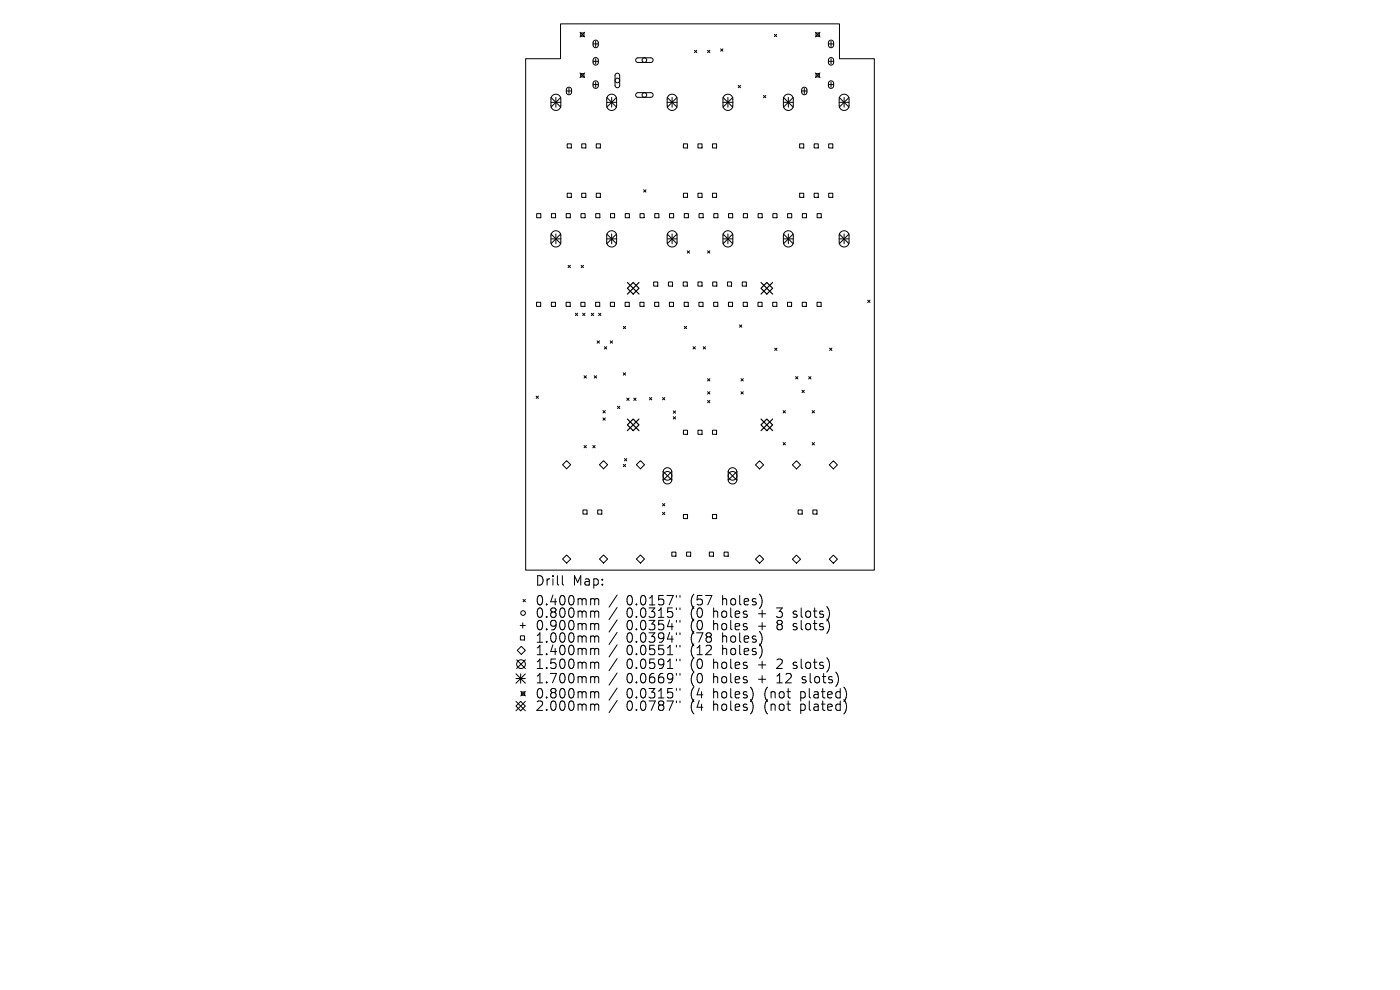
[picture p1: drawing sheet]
<svg xmlns="http://www.w3.org/2000/svg" width="297mm" height="210mm" viewBox="0 0 297 210" stroke-linecap="round" stroke-linejoin="round" font-family="sans-serif">
<defs><g id="words">
<g font-size="2.8">
<text x="113.5" y="124.5">Drill</text>
<text x="121.5" y="124.5">Map:</text>
<text x="113.5" y="128.7">0.400mm</text>
<text x="113.5" y="131.3">0.800mm</text>
<text x="132.9" y="128.7">0.0157&quot;</text>
<text x="132.9" y="131.3">0.0315&quot;</text>
<text x="146.6" y="128.7">(57</text>
<text x="146.6" y="131.3">(0</text>
<text x="151.6" y="131.3">holes</text>
<text x="153.5" y="128.7">holes)</text>
<text x="161.3" y="131.3">+</text>
<text x="165.5" y="131.3">3</text>
<text x="169.1" y="131.3">slots)</text>
<text x="113.5" y="134">0.900mm</text>
<text x="113.5" y="136.6">1.000mm</text>
<text x="132.9" y="134">0.0354&quot;</text>
<text x="132.9" y="136.6">0.0394&quot;</text>
<text x="146.6" y="134">(0</text>
<text x="146.6" y="136.6">(78</text>
<text x="151.6" y="134">holes</text>
<text x="153.5" y="136.6">holes)</text>
<text x="161.3" y="134">+</text>
<text x="165.5" y="134">8</text>
<text x="169.1" y="134">slots)</text>
<text x="113.5" y="139.3">1.400mm</text>
<text x="113.5" y="142.2">1.500mm</text>
<text x="132.9" y="139.3">0.0551&quot;</text>
<text x="132.9" y="142.2">0.0591&quot;</text>
<text x="146.6" y="139.3">(12</text>
<text x="146.6" y="142.2">(0</text>
<text x="151.6" y="142.2">holes</text>
<text x="153.5" y="139.3">holes)</text>
<text x="161.3" y="142.2">+</text>
<text x="165.5" y="142.2">2</text>
<text x="169.1" y="142.2">slots)</text>
<text x="113.5" y="145.2">1.700mm</text>
<text x="113.5" y="148.4">0.800mm</text>
<text x="132.9" y="145.2">0.0669&quot;</text>
<text x="132.9" y="148.4">0.0315&quot;</text>
<text x="146.6" y="145.2">(0</text>
<text x="146.6" y="148.4">(4</text>
<text x="151.6" y="145.2">holes</text>
<text x="151.6" y="148.4">holes)</text>
<text x="161.3" y="145.2">+</text>
<text x="162.6" y="148.4">(not</text>
<text x="165.5" y="145.2">12</text>
<text x="170.5" y="148.4">plated)</text>
<text x="171" y="145.2">slots)</text>
<text x="113.5" y="151.1">2.000mm</text>
<text x="132.9" y="151.1">0.0787&quot;</text>
<text x="146.6" y="151.1">(4</text>
<text x="151.6" y="151.1">holes)</text>
<text x="162.6" y="151.1">(not</text>
<text x="170.5" y="151.1">plated)</text>
</g>
</g></defs>
<g fill="none" stroke="#000" stroke-width=".21">
<path d="M118.9 5.1h59.2v7.4h7.4v108.4h-74v-108.4h7.4zM120.1 19.3h1.2M120.3 18.7l.5-.2 .4 .3v.8l-.3 .4-.4 .1-.3-.3-.1-.8zM120.7 18.7v1.2M123 6.8l1 1M123 15.5l1 1M123.2 7h.7v.7h-.7zM123.2 15.6h.7v.7h-.7zM124 6.8l-1 1M124 15.5l-1 1M125.8 9.3h1.1M125.8 13h1.1"/>
<path d="M125.8 17.9h1.1M126 8.7l.5-.2 .4 .3v.9l-.3 .4h-.4l-.3-.3-.1-.8zM126 12.4l.5-.2 .4 .3v.9l-.3 .4h-.4l-.3-.3-.1-.8zM126 17.3l.5-.1 .4 .3v.8l-.3 .4h-.4l-.3-.3-.1-.8zM126.4 8.8v1.1M126.4 12.5v1.1M126.4 17.4v1.1M130.6 15.7l.5-.1 .4 .3v2.3l-.4 .4-.4-.1-.2-.3v-2.2zM135 12.4l.3-.1h2.8l.3 .1 .2 .4-.5 .4h-2.8l-.4-.3zM135 19.8l.3-.1h2.8l.3 .1 .2 .4-.5 .4h-2.8l-.4-.3zM147.3 10.7l.5 .5M147.8 10.7l-.5 .5"/>
<path d="M150.1 10.7l.5 .5M150.6 10.7l-.5 .5M152.9 10.4l.5 .5M153.4 10.4l-.5 .5M156.6 18.1l.5 .5M157.1 18.1l-.5 .5M164.3 7.3l.5 .5M164.8 7.3l-.5 .5M170.1 19.3h1.1M170.2 18.7l.5-.2 .4 .3 .1 .8-.3 .4-.5 .1-.3-.3v-.8zM170.6 18.7v1.2M173 6.8l1 1"/>
<path d="M173 15.5l1 1M173.1 7h.7v.7h-.7zM173.1 15.6h.7v.7h-.7zM174 6.8l-1 1M174 15.5l-1 1M175.7 9.3h1.2M175.7 13h1.2M175.7 17.9h1.2M175.9 8.7l.5-.2 .4 .3v.9l-.3 .4h-.4l-.3-.3-.1-.8zM175.9 12.4l.5-.2 .4 .3v.9l-.3 .4h-.4l-.3-.3-.1-.8zM175.9 17.3l.5-.1 .4 .3v.8l-.3 .4h-.4l-.3-.3-.1-.8zM176.3 8.8v1.1"/>
<path d="M176.3 12.5v1.1M176.3 17.4v1.1M116.9 20.7l2.1 2.1M116.9 21.7h2.1M117.2 20.3a1.05 1.05 0 0 1 1.1-.2 1.05 1.05 0 0 1 .7 .9v1.4a1.05 1.05 0 0 1-1.1 1 1.05 1.05 0 0 1-1-1v-1.6zM117.9 20.7v2.1M119 20.7l-2.1 2.1M120.3 30.5h.9v.9h-.9zM123.4 30.5h.9v.9h-.9zM126.5 30.5h.9v.9h-.9zM128.7 21.7h2.1M128.7 20.7l2.1 2.1"/>
<path d="M129 20.3a1.05 1.05 0 0 1 1.2-.2 1.05 1.05 0 0 1 .6 .9v1.4a1.05 1.05 0 0 1-1 1 1.05 1.05 0 0 1-1.1-1v-1.6zM129.8 20.7v2.1M130.8 20.7l-2.1 2.1M141.5 21.7h2.1M141.5 20.7l2.1 2.1M141.8 20.3a1.05 1.05 0 0 1 1.2-.2 1.05 1.05 0 0 1 .6 .9v1.4a1.05 1.05 0 0 1-1 1 1.05 1.05 0 0 1-1.1-1l.1-1.6zM142.6 20.7v2.1M143.6 20.7l-2.1 2.1M145 30.5h.9v.9h-.9zM148.1 30.5h.8v.9h-.8zM151.1 30.5h.9v.9h-.9zM153.4 21.7h2.1"/>
<path d="M153.4 20.7l2.1 2.1M153.7 20.3a1.05 1.05 0 0 1 1.1-.2 1.05 1.05 0 0 1 .7 .9v1.4a1.05 1.05 0 0 1-1.1 1 1.05 1.05 0 0 1-1-1v-1.6zM154.4 20.7v2.1M155.5 20.7l-2.1 2.1M162 20.2l.5 .5M162.5 20.2l-.5 .5M166.2 21.7h2.1M166.2 20.7l2.1 2.1M166.5 20.3a1.05 1.05 0 0 1 1.1-.2 1.05 1.05 0 0 1 .7 .9v1.4a1.05 1.05 0 0 1-1.1 1 1.05 1.05 0 0 1-1-1v-1.6zM167.2 20.7v2.1M168.3 20.7l-2.1 2.1M169.6 30.5h.9v.9h-.9z"/>
<path d="M172.7 30.5h.9v.9h-.9zM175.8 30.5h.9v.9h-.9zM178 21.7h2.1M178 20.7l2.1 2.1M178.3 20.3a1.05 1.05 0 0 1 1.2-.2 1.05 1.05 0 0 1 .6 .9v1.4a1.05 1.05 0 0 1-1 1 1.05 1.05 0 0 1-1.1-1v-1.6zM179.1 20.7v2.1M180.1 20.7l-2.1 2.1M113.9 45.3h.8v.9h-.8zM116.9 49.6l2.1 2.1M116.9 50.7h2.1M117 45.3h.9v.9h-.9zM117.2 49.3a1.05 1.05 0 0 1 1.1-.3 1.05 1.05 0 0 1 .7 1v1.4a1.05 1.05 0 0 1-1.1 1 1.05 1.05 0 0 1-1-1v-1.6z"/>
<path d="M117.9 49.6v2.1M119 49.6l-2.1 2.1M120.1 45.3h.9v.9h-.9zM120.3 41h.9v.9h-.9zM120.5 56.3l.5 .5M121 56.3l-.5 .5M123.2 45.3h.9v.9h-.9zM123.3 56.3l.5 .5M123.4 41h.9v.9h-.9zM123.8 56.3l-.5 .5M126.4 45.3h.9v.9h-.9zM126.5 41h.9v.9h-.9z"/>
<path d="M128.7 50.7h2.1M128.7 49.6l2.1 2.1M129 49.3a1.05 1.05 0 0 1 1.2-.3 1.05 1.05 0 0 1 .6 1v1.4a1.05 1.05 0 0 1-1 1 1.05 1.05 0 0 1-1.1-1v-1.6zM129.5 45.3h.9v.9h-.9zM129.8 49.6v2.1M130.8 49.6l-2.1 2.1M132.6 45.3h.9v.9h-.9zM135.8 45.3h.8v.9h-.8zM136.5 40.3l.5 .5M137 40.3l-.5 .5M138.7 59.8h.8v.9h-.8zM138.9 45.3h.9v.9h-.9z"/>
<path d="M141.5 50.7h2.1M141.5 49.6l2.1 2.1M141.8 59.8h.9v.9h-.9zM141.8 49.3a1.05 1.05 0 0 1 1.2-.3 1.05 1.05 0 0 1 .6 1v1.4a1.05 1.05 0 0 1-1 1 1.05 1.05 0 0 1-1.1-1l.1-1.6zM142 45.3h.9v.9h-.9zM142.6 49.6v2.1M143.6 49.6l-2.1 2.1M144.9 59.8h.9v.9h-.9zM145 41h.9v.9h-.9zM145.2 45.3h.8v.9h-.8zM145.8 53.2l.5 .5M146.3 53.2l-.5 .5"/>
<path d="M148.1 41h.8v.9h-.8zM148.1 59.8h.8v.9h-.8zM148.3 45.3h.9v.9h-.9zM150.1 53.2l.5 .5M150.6 53.2l-.5 .5M151.1 41h.9v.9h-.9zM151.2 59.8h.9v.9h-.9zM151.4 45.3h.9v.9h-.9zM153.4 50.7h2.1M153.4 49.6l2.1 2.1M153.7 49.3a1.05 1.05 0 0 1 1.1-.3 1.05 1.05 0 0 1 .7 1v1.4a1.05 1.05 0 0 1-1.1 1 1.05 1.05 0 0 1-1-1v-1.6zM154.3 59.8h.9v.9h-.9z"/>
<path d="M154.4 49.6v2.1M154.6 45.3h.8v.9h-.8zM155.5 49.6l-2.1 2.1M157.5 59.8h.8v.9h-.8zM157.7 45.3h.9v.9h-.9zM160.8 45.3h.9v.9h-.9zM164 45.3h.8v.9h-.8zM166.2 50.7h2.1M166.2 49.6l2.1 2.1M166.5 49.3a1.05 1.05 0 0 1 1.1-.3 1.05 1.05 0 0 1 .7 1v1.4a1.05 1.05 0 0 1-1.1 1 1.05 1.05 0 0 1-1-1v-1.6zM167.1 45.3h.9v.9h-.9zM167.2 49.6v2.1"/>
<path d="M168.3 49.6l-2.1 2.1M169.6 41h.9v.9h-.9zM170.2 45.3h.9v.9h-.9zM172.7 41h.9v.9h-.9zM173.3 45.3h.9v.9h-.9zM175.8 41h.9v.9h-.9zM178 50.7h2.1M178 49.6l2.1 2.1M178.3 49.3a1.05 1.05 0 0 1 1.2-.3 1.05 1.05 0 0 1 .6 1v1.4a1.05 1.05 0 0 1-1 1 1.05 1.05 0 0 1-1.1-1v-1.6zM179.1 49.6v2.1M180.1 49.6l-2.1 2.1M113.8 64.1h.9v.9h-.9z"/>
<path d="M117 64.1h.8v.9h-.8zM120.1 64.1h.9v.9h-.9zM122.1 66.5l.5 .4M122.6 66.5l-.5 .4M123.2 64.1h.9v.9h-.9zM123.6 66.5l.5 .4M123.9 79.7l.5 .5M124.1 66.5l-.5 .4M124.4 79.7l-.5 .5M125.4 66.5l.5 .4M125.9 66.5l-.5 .4M126.1 79.7l.5 .5"/>
<path d="M126.4 64.1h.8v.9h-.8zM126.6 79.7l-.5 .5M126.7 72.3l.5 .5M127 66.5l.5 .4M127.2 72.3l-.5 .5M127.5 66.5l-.5 .4M128.2 73.5l.5 .5M128.7 73.5l-.5 .5M129.5 72.3l.4 .5M129.5 64.1h.9v.9h-.9zM129.9 72.3l-.4 .5M132.2 69.2l.5 .5"/>
<path d="M132.2 79.1l.5 .5M132.6 64.1h.9v.9h-.9zM132.7 69.2l-.5 .5M132.7 79.1l-.5 .5M135.7 64.1h.9v.9h-.9zM138.9 64.1h.9v.9h-.9zM142 64.1h.9v.9h-.9zM145.1 64.1h.9v.9h-.9zM145.2 69.2l.5 .5M145.7 69.2l-.5 .5M147 73.5l.5 .5M147.5 73.5l-.5 .5"/>
<path d="M148.3 64.1h.8v.9h-.8zM149.2 73.5l.5 .5M149.7 73.5l-.5 .5M151.4 64.1h.9v.9h-.9zM154.5 64.1h.9v.9h-.9zM156.9 68.9l.5 .5M157.4 68.9l-.5 .5M157.7 64.1h.8v.9h-.8zM160.8 64.1h.9v.9h-.9zM163.9 64.1h.9v.9h-.9zM164.3 73.9l.5 .4M164.8 73.9l-.5 .4"/>
<path d="M167.1 64.1h.8v.9h-.8zM168.8 79.9l.5 .5M169.3 79.9l-.5 .5M170.2 64.1h.9v.9h-.9zM171.6 79.9l.4 .5M172 79.9l-.4 .5M173.3 64.1h.9v.9h-.9zM176 73.9l.5 .4M176.5 73.9l-.5 .4M184.1 63.7l.5 .5M184.6 63.7l-.5 .5M113.7 84l.5 .5"/>
<path d="M114.2 84l-.5 .5M119.3 98.6l.9-.9 .9 .9-.9 .8zM123.9 94.5l.5 .5M124.4 94.5l-.5 .5M125.8 94.5l.4 .5M126.2 94.5l-.4 .5M127.2 98.6l.8-.9 .9 .9-.9 .8zM127.9 87.1l.5 .5M127.9 88.6l.5 .5M128.4 87.1l-.5 .5M128.4 88.6l-.5 .5M131 86.2l.5 .5"/>
<path d="M131.5 86.2l-.5 .5M132.2 98.5l.5 .5M132.5 97.3l.5 .5M132.7 98.5l-.5 .5M133 97.3l-.5 .5M133 84.5l.5 .4M133.5 84.5l-.5 .4M134.4 84.5l.5 .4M134.9 84.5l-.5 .4M135 98.6l.9-.9 .8 .9-.8 .8zM137.8 84.3l.5 .5M138.3 84.3l-.5 .5"/>
<path d="M140.5 84.3l.5 .5M140.9 99.5a.92 .92 0 0 1 1.1-.2 .92 .92 0 0 1 .5 .8v1.6a.92 .92 0 0 1-.9 1 .92 .92 0 0 1-.9-1v-1.6zM141 84.3l-.5 .5M142.8 87.2l.5 .5M142.8 88.4l.5 .5M143.3 87.2l-.5 .5M143.3 88.4l-.5 .5M145 91.3h.9v.8h-.9zM148.1 91.3h.8v.8h-.8zM150.1 80.3l.5 .5M150.1 83.1l.5 .5M150.1 84.9l.5 .5"/>
<path d="M150.6 80.3l-.5 .5M150.6 83.1l-.5 .5M150.6 84.9l-.5 .5M151.1 91.3h.9v.8h-.9zM154.8 99.5a.92 .92 0 0 1 1-.2 .92 .92 0 0 1 .5 .8v1.6a.92 .92 0 0 1-.9 1 .92 .92 0 0 1-.9-1v-1.6zM157.2 80.3l.5 .5M157.2 83.1l.5 .5M157.7 80.3l-.5 .5M157.7 83.1l-.5 .5M160.3 98.6l.8-.9 .9 .9-.9 .9zM166.1 87.1l.5 .5M166.1 93.9l.5 .5"/>
<path d="M166.6 87.1l-.5 .5M166.6 93.9l-.5 .5M168.1 98.6l.9-.9 .8 .9-.8 .9zM170.1 82.8l.5 .5M170.6 82.8l-.5 .5M172.3 87.1l.5 .5M172.3 93.9l.5 .5M172.8 87.1l-.5 .5M172.8 93.9l-.5 .5M175.9 98.6l.9-.9 .9 .9-.9 .9zM119.3 118.6l.9-.9 .9 .9-.9 .9zM123.7 108.2h.8v.9h-.8z"/>
<path d="M126.8 108.2h.9v.9h-.9zM127.2 118.6l.8-.9 .9 .9-.9 .9zM135 118.6l.9-.9 .8 .9-.8 .9zM140.5 106.8l.5 .5M140.5 108.7l.5 .5M140.7 100l1.8 1.9M141 106.8l-.5 .5M141 108.7l-.5 .5M142.5 117.1h.9v.9h-.9zM142.5 100l-1.8 1.9M145 109.1h.9v.9h-.9zM145.6 117.1h.9v.9h-.9z"/>
<path d="M150.5 117.1h.9v.9h-.9zM151.1 109.1h.9v.9h-.9zM153.6 117.1h.9v.9h-.9zM154.5 100l1.8 1.9M156.3 100l-1.8 1.9M160.3 118.6l.8-.8 .9 .8-.9 .9zM168.1 118.6l.9-.8 .8 .8-.8 .9zM169.3 108.2h.9v.9h-.9zM172.4 108.2h.9v.9h-.9zM175.9 118.6l.9-.8 .9 .8-.9 .9zM109.6 140l1.9 1.8M109.7 138l.9-.9 .9 .9-.9 .8z"/>
<path d="M110.3 132.7h1.2M110.4 134.9h.9v.9h-.9zM110.9 132.1v1.1M111 127.2l.5 .5M111.5 127.2l-.5 .5M111.5 140l-1.9 1.8M119.3 122.1v1.7l.3 .3M125.6 127h.3l.3 .3M125.6 129.6h.3l.3 .3M125.6 132.3h.3l.3 .3M125.6 134.9h.3l.3 .3M125.6 137.5h.3l.3 .3"/>
<path d="M126.2 127.3l.2-.3 .5 .1 .1 1.2M126.2 127.3v1M126.2 129.9v1.1M126.2 132.6v1M126.2 135.2v1M126.2 137.8v1.1M126.2 129.9l.2-.3 .5 .1 .1 1.3M126.2 132.6l.2-.3 .5 .1 .1 1.2M126.2 135.2l.2-.3 .5 .1 .1 1.2M126.2 137.8l.2-.3 .5 .1 .1 1.3M130.9 126.2l-1.7 2.6M130.9 128.9l-1.7 2.5"/>
<path d="M130.9 131.5l-1.7 2.6M130.9 134.1l-1.7 2.6M130.9 136.8l-1.7 2.6M130.9 139.7l-1.7 2.6M143.5 126.3v.4M143.5 129v.3M143.5 131.6v.4M143.5 134.2v.4M143.5 136.9v.4M143.5 139.8v.4M144.3 126.3v.4M144.3 129v.3"/>
<path d="M144.3 131.6v.4M144.3 134.2v.4M144.3 136.9v.4M144.3 139.8v.4M168.3 130.9l.1 .1M168.3 133.5l.1 .1M168.3 129.7v.5M168.3 132.4v.4M109.5 142.9l2 2M109.5 143.9h2M109.5 148.8l2 2M110.5 148.8l1 1-1 1-1-1z"/>
<path d="M110.5 142.9v2M110.5 146.6l1 1M110.6 146.8h.7v.7h-.7zM111.5 142.9l-2 2M111.5 146.6l-1 1M111.5 148.8l-2 2M125.6 140.5h.3l.3 .3M125.6 143.5h.3l.3 .3M125.6 146.7h.3l.3 .3M125.6 149.4h.3l.3 .2M126.2 140.8v1M126.2 143.8v1.1"/>
<path d="M126.2 147v1.1M126.2 149.6v1.1M126.2 140.8l.2-.3 .5 .1 .1 1.2M126.2 143.8l.2-.3 .5 .1 .1 1.3M126.2 147l.2-.3 .5 .1 .1 1.3M126.2 149.6l.2-.2 .5 .1 .1 1.2M130.9 142.8l-1.7 2.5M130.9 146l-1.7 2.5M130.9 148.6l-1.7 2.6M143.5 142.9v.3M143.5 146.1v.3M143.5 148.7v.4"/>
<path d="M144.3 142.9v.3M144.3 146.1v.3M144.3 148.7v.4M168.3 141.7l.1 .1M168.3 140.6v.4M170.2 144.8l.1 .1M170.3 143.6v.5"/>
<circle cx="131" cy="17.1" r=".49"/>
<circle cx="136.7" cy="12.8" r=".49"/>
<circle cx="136.7" cy="20.2" r=".49"/>
<circle cx="141.6" cy="100.9" r=".92"/>
<circle cx="155.4" cy="100.9" r=".92"/>
<circle cx="111" cy="130" r=".49"/>
<circle cx="110.5" cy="140.9" r=".92"/>
</g>
<path d="M133.1 59.9l2.5 2.5M134.3 59.9l1.3 1.3-1.3 1.2-1.2-1.2zM135.6 59.9l-2.5 2.5M161.4 59.9l2.5 2.5M163.9 59.9l-2.5 2.5M161.4 61.2l1.3-1.3 1.2 1.3-1.2 1.2zM133.1 88.9l2.5 2.5M134.3 88.9l1.3 1.2-1.3 1.3-1.2-1.3zM135.6 88.9l-2.5 2.5M161.4 90.1l1.3-1.2 1.2 1.2-1.2 1.3zM161.4 88.9l2.5 2.5M163.9 88.9l-2.5 2.5" fill="none" stroke="#000" stroke-width=".25"/>
<use href="#words"/>
</svg>
